VERSION 5.8 ;
BUSBITCHARS "[]" ;
DIVIDERCHAR "/" ;
UNITS
    DATABASE MICRONS 1000 ;
END UNITS

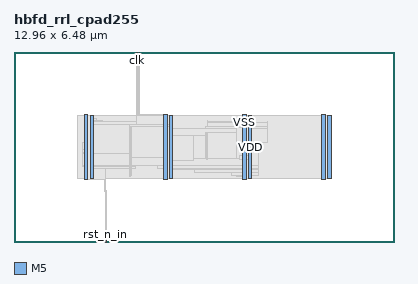
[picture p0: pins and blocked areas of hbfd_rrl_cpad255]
MACRO hbfd_rrl_cpad255
  FOREIGN hbfd_rrl_cpad255 0 0 ;
  CLASS BLOCK ;
  SIZE 12.96 BY 6.48 ;
  PIN clk
    DIRECTION INPUT ;
    USE SIGNAL ;
    PORT
      LAYER M5 ;
        RECT  4.176 6.396 4.2 6.48 ;
    END
  END clk
  PIN rst_n
    DIRECTION OUTPUT ;
    USE SIGNAL ;
    PORT
      LAYER M5 ;
        RECT  4.272 6.396 4.296 6.48 ;
    END
  END rst_n
  PIN rst_n_in
    DIRECTION INPUT ;
    USE SIGNAL ;
    PORT
      LAYER M5 ;
        RECT  3.12 0 3.144 0.084 ;
    END
  END rst_n_in
  PIN VDD
    DIRECTION INOUT ;
    USE POWER ;
    PORT
      LAYER M5 ;
        RECT  10.692 2.151 10.812 4.329 ;
        RECT  7.992 2.151 8.112 4.329 ;
        RECT  5.292 2.151 5.412 4.329 ;
        RECT  2.592 2.151 2.712 4.329 ;
    END
  END VDD
  PIN VSS
    DIRECTION INOUT ;
    USE GROUND ;
    PORT
      LAYER M5 ;
        RECT  10.5 2.137 10.62 4.343 ;
        RECT  7.8 2.137 7.92 4.343 ;
        RECT  5.1 2.137 5.22 4.343 ;
        RECT  2.4 2.137 2.52 4.343 ;
    END
  END VSS
  OBS
    LAYER RVTN ;
     RECT  2.16 2.16 10.8 2.295 ;
     RECT  2.16 2.565 10.8 2.835 ;
     RECT  2.16 3.105 10.8 3.375 ;
     RECT  2.16 3.645 10.8 3.915 ;
     RECT  2.16 4.185 10.8 4.32 ;
    LAYER RVTP ;
     RECT  2.16 2.295 10.8 2.565 ;
     RECT  2.16 2.835 10.8 3.105 ;
     RECT  2.16 3.375 10.8 3.645 ;
     RECT  2.16 3.915 10.8 4.185 ;
    LAYER M1 ;
     RECT  2.16 2.151 10.8 4.329 ;
    LAYER M2 ;
     RECT  2.16 2.151 10.8 4.329 ;
     RECT  10.8 2.421 10.812 4.059 ;
    LAYER M3 ;
     RECT  3.096 1.723 3.114 2.143 ;
     RECT  7.815 2.143 7.905 2.227 ;
     RECT  7.596 2.227 7.905 2.263 ;
     RECT  7.416 2.263 8.334 2.371 ;
     RECT  5.115 2.143 5.205 2.413 ;
     RECT  10.515 2.143 10.605 2.413 ;
     RECT  5.115 2.413 5.397 2.461 ;
     RECT  6.156 2.371 8.334 2.461 ;
     RECT  2.415 2.143 3.114 2.497 ;
     RECT  3.96 2.251 3.978 2.497 ;
     RECT  5.115 2.461 8.334 2.497 ;
     RECT  2.415 2.497 4.158 2.569 ;
     RECT  2.34 2.569 4.158 2.605 ;
     RECT  4.896 2.497 8.334 2.605 ;
     RECT  2.34 2.605 8.334 3.145 ;
     RECT  2.34 3.145 8.442 3.379 ;
     RECT  2.34 3.379 8.658 3.407 ;
     RECT  2.415 3.407 8.658 3.875 ;
     RECT  6.516 3.875 8.658 3.947 ;
     RECT  5.112 3.875 5.397 3.983 ;
     RECT  5.115 3.983 5.397 4.067 ;
     RECT  6.588 3.947 8.658 4.067 ;
     RECT  10.515 2.413 10.797 4.067 ;
     RECT  2.415 3.875 4.302 4.109 ;
     RECT  6.588 4.067 7.905 4.109 ;
     RECT  8.64 4.067 8.658 4.109 ;
     RECT  2.415 4.109 3.006 4.145 ;
     RECT  6.588 4.109 6.606 4.145 ;
     RECT  7.704 4.109 7.905 4.145 ;
     RECT  2.415 4.145 2.826 4.217 ;
     RECT  2.415 4.217 2.505 4.337 ;
     RECT  5.115 4.067 5.205 4.337 ;
     RECT  7.815 4.145 7.905 4.337 ;
     RECT  10.515 4.067 10.605 4.337 ;
     RECT  4.248 4.109 4.266 6.365 ;
    LAYER M4 ;
     RECT  2.329 3.024 2.408 3.048 ;
     RECT  2.408 2.148 2.512 4.332 ;
     RECT  2.512 2.148 2.704 4.062 ;
     RECT  3.085 1.728 3.169 1.752 ;
     RECT  2.704 3.024 3.925 4.008 ;
     RECT  3.925 2.256 3.971 4.008 ;
     RECT  3.971 2.256 4.012 3.96 ;
     RECT  4.237 6.336 4.321 6.36 ;
     RECT  4.012 2.88 5.108 3.96 ;
     RECT  5.108 2.148 5.212 4.332 ;
     RECT  5.212 2.418 5.404 4.062 ;
     RECT  5.404 2.784 6.113 3.624 ;
     RECT  6.113 2.832 6.533 3.624 ;
     RECT  6.533 2.832 7.585 3.72 ;
     RECT  7.585 2.832 7.808 3.912 ;
     RECT  7.808 2.148 7.912 4.332 ;
     RECT  7.912 2.418 8.104 4.062 ;
     RECT  10.508 2.148 10.612 4.332 ;
     RECT  10.612 2.418 10.804 4.062 ;
    LAYER M5 ;
     RECT  3.12 0.016 3.144 1.763 ;
     RECT  5.1 2.137 5.22 2.151 ;
     RECT  7.8 2.137 7.92 2.151 ;
     RECT  10.5 2.137 10.62 2.151 ;
     RECT  7.8 2.151 8.112 2.821 ;
     RECT  7.68 2.821 8.112 2.963 ;
     RECT  6.576 2.821 6.6 3.731 ;
     RECT  3.936 2.245 3.96 3.925 ;
     RECT  5.1 2.151 5.412 3.925 ;
     RECT  3.936 3.925 5.412 4.019 ;
     RECT  2.4 2.137 2.712 4.329 ;
     RECT  4.176 4.019 5.412 4.329 ;
     RECT  7.8 2.963 8.112 4.329 ;
     RECT  10.5 2.151 10.812 4.329 ;
     RECT  2.4 4.329 2.52 4.343 ;
     RECT  4.176 4.329 5.22 4.343 ;
     RECT  7.8 4.329 7.92 4.343 ;
     RECT  10.5 4.329 10.62 4.343 ;
     RECT  4.176 4.343 4.2 6.325 ;
     RECT  4.176 6.325 4.296 6.416 ;
  END
END hbfd_rrl_cpad255
END LIBRARY
